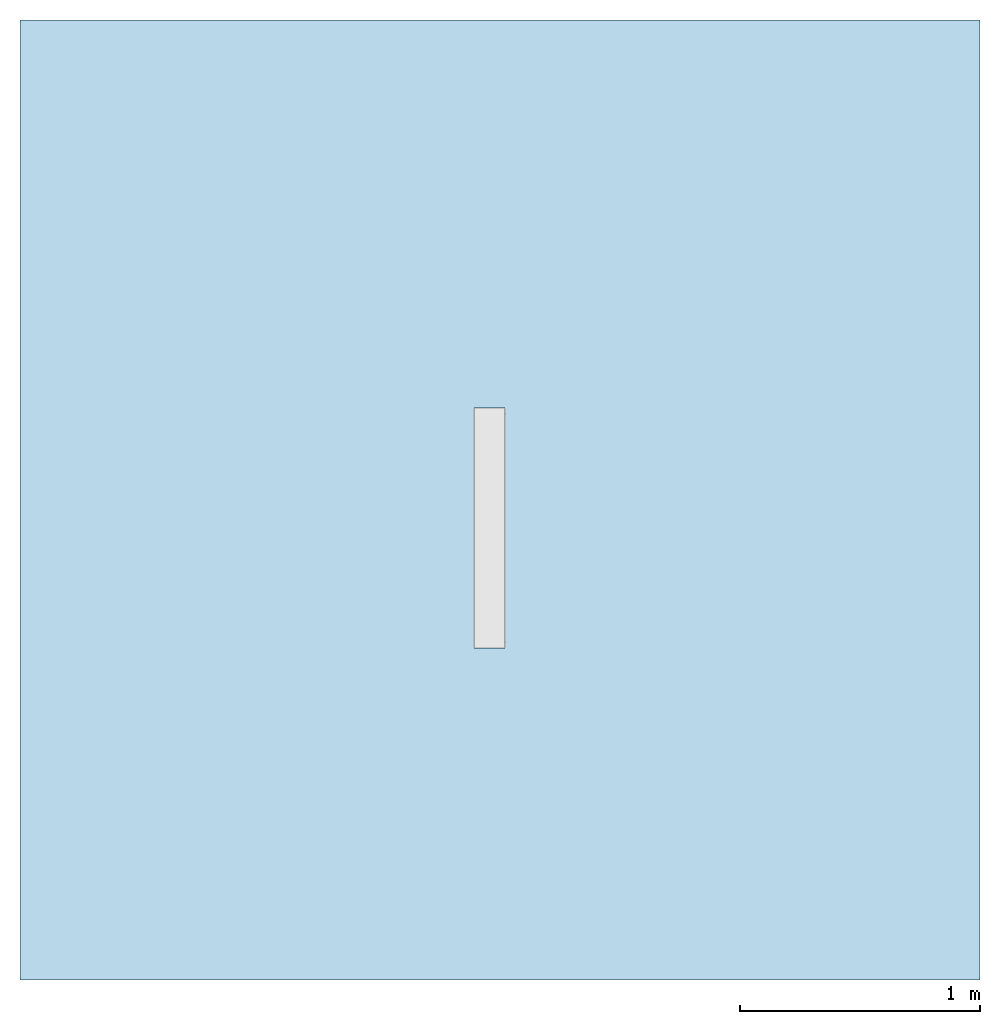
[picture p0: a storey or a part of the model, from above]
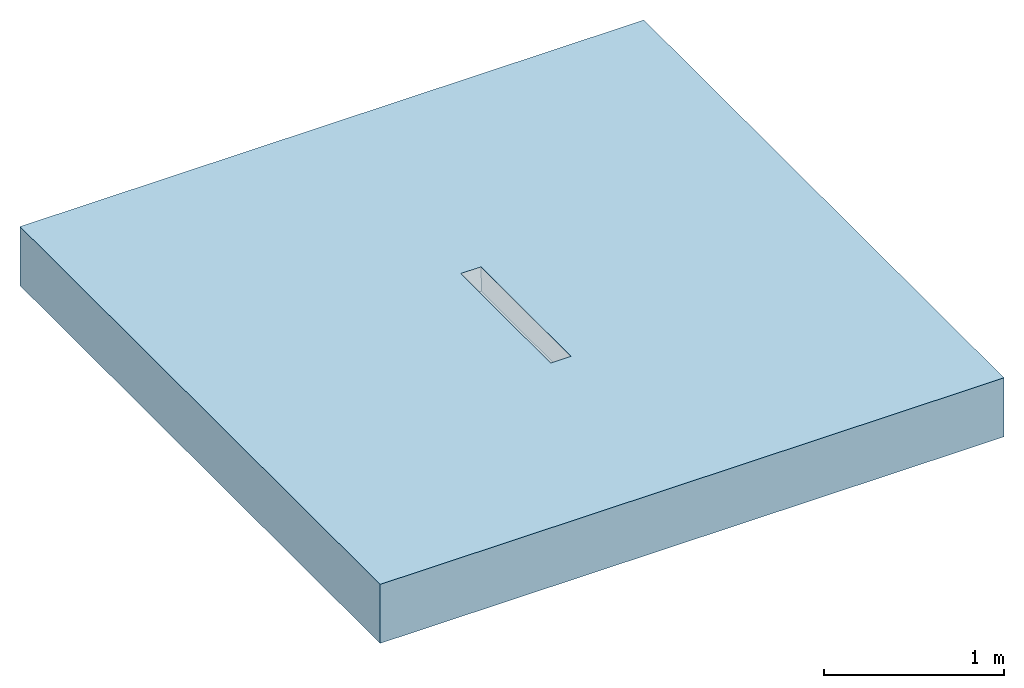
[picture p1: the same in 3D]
Properties of the parts of a building model (IFC2X3)

# File
Description: ViewDefinition [CoordinationView]
File name: Project Number
Time: 2014-06-06T12:53:36
Written by: The EXPRESS Data Manager Version 5.01.0100.02.64mod : 6 Jun 2012
Made in: 20130308_1515(x64) - Exporter 2014.0.2013.0308 - Default UI
Comment: STEP Physical File produced by: The EXPRESS Data Manager Version 5.01.0100.02.64mod : 6 Jun 2012 * Module: EDMstepFileFactory/EDMstandAlone * Creation date: Fri Jun 06 12:53:36 2014 * Host: IN-BLR-PC-0010 * Database: C:\Users\palleri\AppData\Local\Temp\{9435408B-DFF7-406C-AE22-E4441796099C}\ifc * Database version: 5507 * Database creation date: Fri Jun 06 12:53:34 2014 * Schema: IFC2X3 * Model: DataRepository.ifc * Model creation date: Fri Jun 06 12:53:35 2014 * Header model: DataRepository.ifc_HeaderModel * Header model creation date: Fri Jun 06 12:53:35 2014 * EDMuser: sdai-user * EDMgroup: sdai-group * License ID and type: 5605 : Permanent license. Expiry date: * EDMstepFileFactory options: 020000

# IfcProject, Project Number
LongName: Project Name; Phase: Project Status

# IfcSite, Default
RefLatitude: 42, 21, 30, 344238; RefLongitude: -71, -3, -35, -194702; RefElevation: 0 mm

# IfcBuilding
Pset_BuildingCommon - NumberOfStoreys: 1
Other - Project Number: Project Number; Client Name: Owner; Project Name: Project Name; Project Address: ## Street City, State Zip; Project Issue Date: Issue Date; Project Status: Project Status

# IfcBuildingStorey, Level 1
LongName: Level 1; Elevation: 0 mm
Constraints - Elevation Base: Project Base Point; Elevation: 0 mm
Graphics - Line Pattern: Center; Line Weight: 1; Symbol at End 2 Default: yes; Symbol: M_Level Head - Circle: M_Level Head - Circle; Color: 0; Symbol at End 1 Default: no
Identity Data - Building Story: yes; Structural: no; Name: Level 1
Dimensions - Computation Height: 0 mm

# IfcFlowTerminal: 36854 - Adjustable Channel - Deep Section - 1000mm LG - Invert Depth 105/165mm, ACO Freedeck Adjustable Height Channel Deep Section - Stainless Steel:36854 - Adjustable Channel - Deep Section - 1000mm LG - Invert Depth 105/165mm:305299
In: Level 1
Material: Stainless Steel Grade 304
Other - Top Piece Void Height @ Invert 1: 75 mm; Top Piece Void Height @ Invert 2: 75 mm; Height @ Invert 1 Min & Max: 165 mm; Height @ Invert 2 Min & Max: 165 mm; Side Void Adjustment: 25 mm; Nos: 32
Identity Data - Mark: 27; Watermarked By: www.acobd.com; Manufacturer: ACO Building Drainage; Telephone: +44 (0)1462 816666; E-mail Sales: abdcommercial@aco.co.uk; Watermark2: This file is water marked and users are prohibited to reproduce, adapt, distribute this information; Website: www.acobd.com; Address: ACO Business Centre, Caxton Road, Bedford, MK41 0LF; Watermark1: This file is the property of ACO Technologies PLC; Watermarked With: BIM Manager Premium Suite; Fax: +44 (0)1462 851490; E-mail Technical: abdtechnical@aco.co.uk
Construction - End Plate Invert 1: no; End Plate Invert 2: no; 00273 - Grating - Slotted Grating - Stainless Steel 304 - 500mm long: no; 36954 - Grating - Plain Mesh - Stainless Steel 304 - 500mm long: no; 00272 - Grating - Slotted Grating - Stainless Steel 304 - 1000mm long: no; 36955 - Grating - Plain Mesh - Stainless Steel 304 - 1000mm long: yes
Phasing - Phase Created: New Construction
Constraints - Moves With Nearby Elements: no; Level: Level: Level 1
Dimensions - Height @ Invert 1: 165 mm; Height @ Invert 2: 165 mm; Viod Start: 55 mm; Viod End: 50 mm; Grating End Length: 1000 mm; Channel End Length: -1000 mm
Pset_ManufacturerTypeInformation - Manufacturer: ACO Building Drainage
General - Product Type: Linear Deck Drainage System; Channel Colour: Mid Grey; Product Standard: BS EN 1433:2002, CE marked; Dimensions (LxWxH): 1000 x 130 x 105/165; Installation Guidelines: X:\Electronic Literature\ABD Electronic Literature\Roof and Balcony Drainage\ACO Freedeck Brochure.pdf; Weight (Kg): 6.4kg; Channel Material: Stainless Steel Grade 304; Load Class: A15; Price: POA - contact ACO; Product Range: ACO Freedeck; NBS Specification: NBS Section R10 Gravity Rainwater Drainage Systems, Subsection 365; Channel Recycled Material Content: 60 - 70 %; Product Description: ACO Freedeck Adjustable Channel - Deep Section; Channel Recyclable: Fully recyclable; Product Code: 36854; Maintenance Guidelines: X:\Electronic Literature\ABD Electronic Literature\Roof and Balcony Drainage\ACO Freedeck Brochure.pdf
Model Properties - Grating Product Code 00272: Load Class A15 - Slotted Grating - 10 x 80mm Slot - Stainless Steel 304 - 1000mm long - 2.2kg; Grating Product Code 00273: Load Class A15 - Slotted Grating - 10 x 80mm Slot - Stainless Steel 304 - 500mm long - 1.0kg; End Plate Product Code 36859: End Plate Stainless Steel 304 for Invert Depth - 105/165mm - 0.2Kg; Grating Product Code 36955: Load Class A15 - Mesh Grating - 14mm x 30mm Mesh - Stainless Steel 304 - 1000mm long - 3.0kg; Grating Product Code 36954: Load Class A15 - Mesh Grating - 14mm x 30mm Mesh - Stainless Steel 304 - 500mm long - 1.6kg
Materials and Finishes - Material: Stainless Steel Grade 304

# IfcOpeningElement: Recess
In: Level 1
Constraints - Height Offset From Level: 0 mm; Level: Level: Level 1; Related to Mass: no; Room Bounding: yes
Phasing - Phase Created: New Construction
Dimensions - Thickness: 400 mm; Perimeter: 16000 mm; Area: 16 m2; Volume: 6.37819 m3
Structural - Structural: no; Enable Analytical Model: no
Materials and Finishes - Structural Material: Concrete, Broom Finish
Graphics - Coarse Scale Fill Color: 0
Analytical Properties - Heat Transfer Coefficient (U): 2.615; Roughness: 1; Absorptance: 0.1; Thermal mass: 604440; Thermal Resistance (R): 0.382409
Construction - Function: Interior; Default Thickness: 400 mm

# IfcSlab: Floor:Generic Floor - 400mm, Floor:Generic Floor - 400mm:193825
In: Level 1
PredefinedType: FLOOR; Material: Concrete, Broom Finish 400 mm
Constraints - Height Offset From Level: 0 mm; Level: Level: Level 1; Related to Mass: no; Room Bounding: yes
Phasing - Phase Created: New Construction
Dimensions - Thickness: 400 mm; Perimeter: 16000 mm; Area: 16 m2; Volume: 6.37819 m3
Structural - Structural: no; Enable Analytical Model: no
Pset_SlabCommon - Reference: Generic Floor - 400mm; IsExternal: no; LoadBearing: yes; ThermalTransmittance: 2.615 kg/K/s3
Materials and Finishes - Structural Material: Concrete, Broom Finish
Graphics - Coarse Scale Fill Color: 0
Analytical Properties - Heat Transfer Coefficient (U): 2.615; Roughness: 1; Absorptance: 0.1; Thermal mass: 604440; Thermal Resistance (R): 0.382409
Construction - Function: Interior; Default Thickness: 400 mm
